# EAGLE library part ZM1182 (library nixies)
ZM1182: medium numeric topview nixie tube

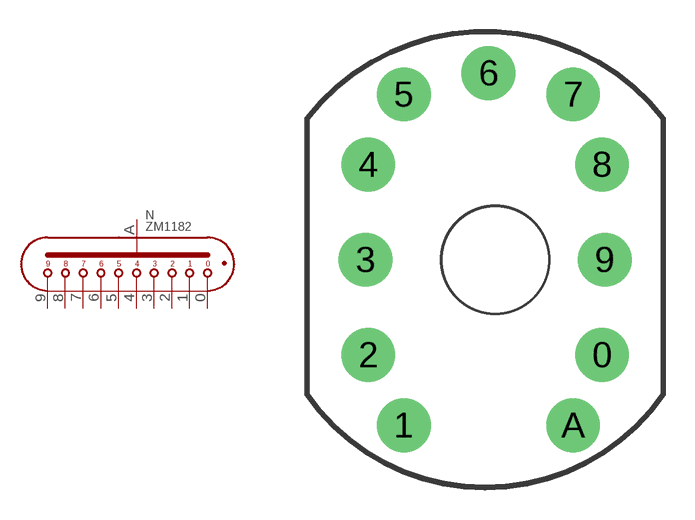
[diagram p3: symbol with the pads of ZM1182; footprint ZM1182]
Designator prefix N

## ZM1182  [ZM1182]
0  0  pas
1  1  pas
2  2  pas
3  3  pas
4  4  pas
5  5  pas
6  6  pas
7  7  pas
8  8  pas
9  9  pas
A  A  pas

## Footprint ZM1182 (pad centres in mm)
May be used with socket: SK-136
drill 1.1 pad 2.54 round: 0 5.048,-4.5; 1 -4.317,-7.817; 2 -6,-4.5; 3 -6.127,0; 4 -6,4.5; 5 -4.317,7.817; 6 -0.318,8.818; 7 3.683,7.817; 8 5.048,4.5; 9 5.175,0; A 3.683,-7.817
hole 5 at 0,0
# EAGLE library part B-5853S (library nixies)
B-5853S The low priced side-viewing Nixie tube, high quality, cold-cathode indicator tube having a common anode. It can display the numerals 0-9 and have two decimal points. 170Vdc, 14ma, 0.5w

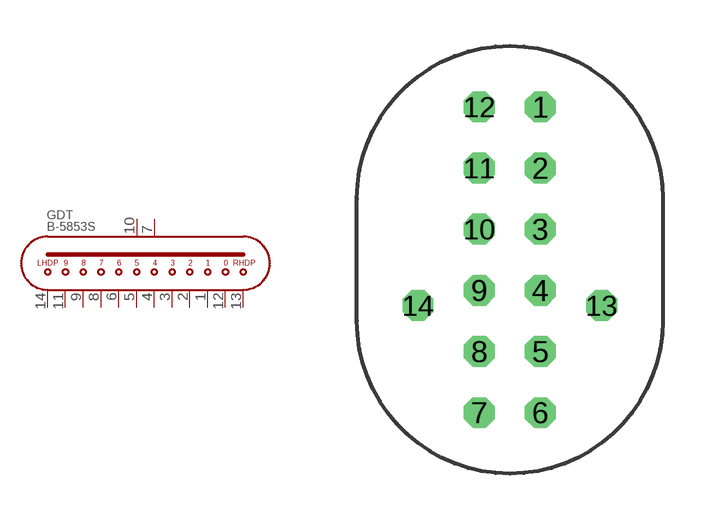
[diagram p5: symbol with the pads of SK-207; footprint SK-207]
Designator prefix GDT

## B-5853S  [SK-207]
1  1  pas
2  2  pas
3  3  pas
4  4  pas
5  5  pas
6  6  pas
7  7  pas
8  8  pas
9  9  pas
10  10  pas
11  11  pas
12  12  pas
13  13  pas
14  14  pas

## Footprint SK-207 (pad centres in mm)
SK-207 Socket The SK-207 Sockets are intented for use with Burroughs B-5750S and B-5850S Nixie tubes.
drill 0.5 octagon: 1 1,5; 2 1,3; 3 1,1; 4 1,-1; 5 1,-3; 6 1,-5; 7 -1,-5; 8 -1,-3; 9 -1,-1; 10 -1,1; 11 -1,3; 12 -1,5; 13 3,-1.5; 14 -3,-1.5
